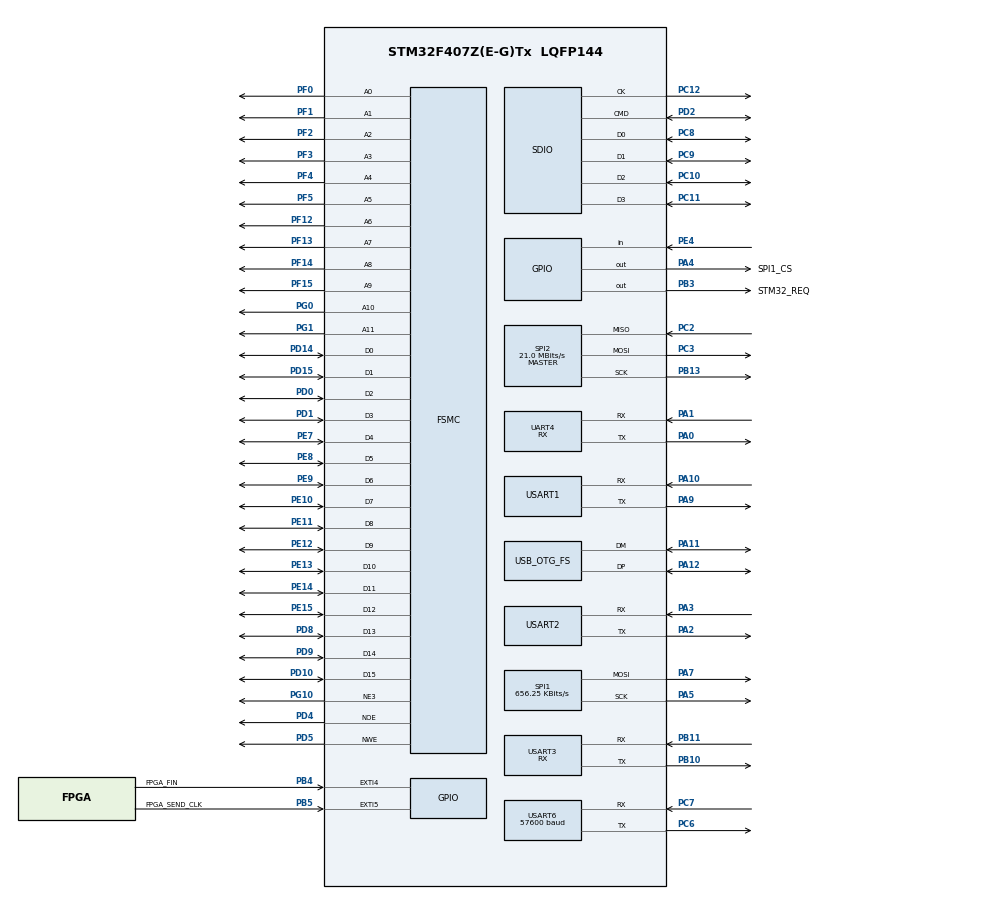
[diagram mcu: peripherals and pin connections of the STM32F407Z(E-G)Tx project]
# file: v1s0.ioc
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Dma.Request0=USART1_RX
Dma.Request1=SDIO_RX
Dma.Request2=SDIO_TX
Dma.Request3=USART1_TX
Dma.Request4=USART3_RX
Dma.Request5=UART4_RX
Dma.Request6=USART6_RX
Dma.SDIO_RX.1.Direction=DMA_PERIPH_TO_MEMORY
Dma.SDIO_RX.1.FIFOMode=DMA_FIFOMODE_ENABLE
Dma.SDIO_RX.1.FIFOThreshold=DMA_FIFO_THRESHOLD_FULL
Dma.SDIO_RX.1.Instance=DMA2_Stream3
Dma.SDIO_RX.1.MemBurst=DMA_MBURST_INC4
Dma.SDIO_RX.1.MemDataAlignment=DMA_MDATAALIGN_WORD
Dma.SDIO_RX.1.MemInc=DMA_MINC_ENABLE
Dma.SDIO_RX.1.Mode=DMA_PFCTRL
Dma.SDIO_RX.1.PeriphBurst=DMA_PBURST_INC4
Dma.SDIO_RX.1.PeriphDataAlignment=DMA_PDATAALIGN_WORD
Dma.SDIO_RX.1.PeriphInc=DMA_PINC_DISABLE
Dma.SDIO_RX.1.Priority=DMA_PRIORITY_VERY_HIGH
Dma.SDIO_TX.2.Direction=DMA_MEMORY_TO_PERIPH
Dma.SDIO_TX.2.FIFOMode=DMA_FIFOMODE_ENABLE
Dma.SDIO_TX.2.FIFOThreshold=DMA_FIFO_THRESHOLD_FULL
Dma.SDIO_TX.2.Instance=DMA2_Stream6
Dma.SDIO_TX.2.MemBurst=DMA_MBURST_INC4
Dma.SDIO_TX.2.MemDataAlignment=DMA_MDATAALIGN_WORD
Dma.SDIO_TX.2.MemInc=DMA_MINC_ENABLE
Dma.SDIO_TX.2.Mode=DMA_PFCTRL
Dma.SDIO_TX.2.PeriphBurst=DMA_PBURST_INC4
Dma.SDIO_TX.2.PeriphDataAlignment=DMA_PDATAALIGN_WORD
Dma.SDIO_TX.2.PeriphInc=DMA_PINC_DISABLE
Dma.SDIO_TX.2.Priority=DMA_PRIORITY_VERY_HIGH
Dma.UART4_RX.5.Direction=DMA_PERIPH_TO_MEMORY
Dma.UART4_RX.5.FIFOMode=DMA_FIFOMODE_DISABLE
Dma.UART4_RX.5.Instance=DMA1_Stream2
Dma.UART4_RX.5.MemDataAlignment=DMA_MDATAALIGN_BYTE
Dma.UART4_RX.5.MemInc=DMA_MINC_ENABLE
Dma.UART4_RX.5.Mode=DMA_CIRCULAR
Dma.UART4_RX.5.PeriphDataAlignment=DMA_PDATAALIGN_BYTE
Dma.UART4_RX.5.PeriphInc=DMA_PINC_DISABLE
Dma.UART4_RX.5.Priority=DMA_PRIORITY_MEDIUM
Dma.USART1_RX.0.Direction=DMA_PERIPH_TO_MEMORY
Dma.USART1_RX.0.FIFOMode=DMA_FIFOMODE_DISABLE
Dma.USART1_RX.0.Instance=DMA2_Stream2
Dma.USART1_RX.0.MemDataAlignment=DMA_MDATAALIGN_BYTE
Dma.USART1_RX.0.MemInc=DMA_MINC_ENABLE
Dma.USART1_RX.0.Mode=DMA_CIRCULAR
Dma.USART1_RX.0.PeriphDataAlignment=DMA_PDATAALIGN_BYTE
Dma.USART1_RX.0.PeriphInc=DMA_PINC_DISABLE
Dma.USART1_RX.0.Priority=DMA_PRIORITY_LOW
Dma.USART1_TX.3.Direction=DMA_MEMORY_TO_PERIPH
Dma.USART1_TX.3.FIFOMode=DMA_FIFOMODE_DISABLE
Dma.USART1_TX.3.Instance=DMA2_Stream7
Dma.USART1_TX.3.MemDataAlignment=DMA_MDATAALIGN_BYTE
Dma.USART1_TX.3.MemInc=DMA_MINC_ENABLE
Dma.USART1_TX.3.Mode=DMA_NORMAL
Dma.USART1_TX.3.PeriphDataAlignment=DMA_PDATAALIGN_BYTE
Dma.USART1_TX.3.PeriphInc=DMA_PINC_DISABLE
Dma.USART1_TX.3.Priority=DMA_PRIORITY_LOW
Dma.USART3_RX.4.Direction=DMA_PERIPH_TO_MEMORY
Dma.USART3_RX.4.FIFOMode=DMA_FIFOMODE_DISABLE
Dma.USART3_RX.4.Instance=DMA1_Stream1
Dma.USART3_RX.4.MemDataAlignment=DMA_MDATAALIGN_BYTE
Dma.USART3_RX.4.MemInc=DMA_MINC_ENABLE
Dma.USART3_RX.4.Mode=DMA_CIRCULAR
Dma.USART3_RX.4.PeriphDataAlignment=DMA_PDATAALIGN_BYTE
Dma.USART3_RX.4.PeriphInc=DMA_PINC_DISABLE
Dma.USART3_RX.4.Priority=DMA_PRIORITY_MEDIUM
Dma.USART6_RX.6.Direction=DMA_PERIPH_TO_MEMORY
Dma.USART6_RX.6.FIFOMode=DMA_FIFOMODE_DISABLE
Dma.USART6_RX.6.Instance=DMA2_Stream1
Dma.USART6_RX.6.MemDataAlignment=DMA_MDATAALIGN_BYTE
Dma.USART6_RX.6.MemInc=DMA_MINC_ENABLE
Dma.USART6_RX.6.Mode=DMA_CIRCULAR
Dma.USART6_RX.6.PeriphDataAlignment=DMA_PDATAALIGN_BYTE
Dma.USART6_RX.6.PeriphInc=DMA_PINC_DISABLE
Dma.USART6_RX.6.Priority=DMA_PRIORITY_HIGH
FATFS.BSP.number=1
FATFS.USE_DMA_CODE_SD=1
FATFS._CODE_PAGE=936
FATFS._USE_LFN=2
FATFS0.BSP.STBoard=false
FATFS0.BSP.api=Unknown
FATFS0.BSP.i2caddr=0
FATFS0.BSP.instance=PE4
FATFS0.BSP.ip=GPIO
FATFS0.BSP.mode=Input
FATFS0.BSP.name=Detect_SDIO
FATFS0.BSP.solution=PE4
FSMC.AddressSetupTime1=0
FSMC.BusTurnAroundDuration1=0
FSMC.DataSetupTime1=8
FSMC.ExtendedMode1=FSMC_EXTENDED_MODE_DISABLE
FSMC.WriteOperation1=FSMC_WRITE_OPERATION_ENABLE
Mcu.Family=STM32F4
Mcu.Name=STM32F407Z(E-G)Tx
Mcu.Package=LQFP144
NVIC.DMA1_Stream1_IRQn=true\:7\:0\:true\:false\:true\:false\:true
NVIC.DMA1_Stream2_IRQn=true\:7\:0\:true\:false\:true\:false\:true
NVIC.DMA2_Stream1_IRQn=true\:6\:0\:true\:false\:true\:false\:true
NVIC.DMA2_Stream2_IRQn=true\:15\:0\:true\:false\:true\:false\:true
NVIC.DMA2_Stream3_IRQn=true\:3\:0\:true\:false\:true\:false\:true
NVIC.DMA2_Stream6_IRQn=true\:3\:0\:true\:false\:true\:false\:true
NVIC.DMA2_Stream7_IRQn=true\:15\:0\:true\:false\:true\:false\:true
NVIC.EXTI4_IRQn=true\:0\:0\:true\:false\:true\:true\:true
NVIC.EXTI9_5_IRQn=true\:5\:0\:true\:false\:true\:true\:true
NVIC.OTG_FS_IRQn=true\:14\:0\:true\:false\:true\:true\:true
NVIC.PriorityGroup=NVIC_PRIORITYGROUP_4
NVIC.SDIO_IRQn=true\:2\:0\:true\:false\:true\:true\:true
NVIC.TIM2_IRQn=true\:4\:0\:true\:false\:true\:true\:true
NVIC.UART4_IRQn=true\:7\:0\:true\:false\:true\:true\:true
NVIC.USART1_IRQn=true\:15\:0\:true\:false\:true\:true\:true
NVIC.USART3_IRQn=true\:7\:0\:true\:false\:true\:true\:true
NVIC.USART6_IRQn=true\:6\:0\:true\:false\:true\:true\:true
PA0-WKUP.Mode=Asynchronous
PA0-WKUP.Signal=UART4_TX
PA1.Mode=Asynchronous
PA1.Signal=UART4_RX
PA10.Mode=Asynchronous
PA10.Signal=USART1_RX
PA11.Mode=Device_Only
PA11.Signal=USB_OTG_FS_DM
PA12.Mode=Device_Only
PA12.Signal=USB_OTG_FS_DP
PA13.Mode=Serial_Wire
PA13.Signal=SYS_JTMS-SWDIO
PA14.Mode=Serial_Wire
PA14.Signal=SYS_JTCK-SWCLK
PA2.Mode=Asynchronous
PA2.Signal=USART2_TX
PA3.Mode=Asynchronous
PA3.Signal=USART2_RX
PA4.GPIO_Label=SPI1_CS
PA4.Signal=GPIO_Output
PA5.Mode=TX_Only_Simplex_Unidirect_Master
PA5.Signal=SPI1_SCK
PA7.GPIO_PuPd=GPIO_PULLUP
PA7.Mode=TX_Only_Simplex_Unidirect_Master
PA7.Signal=SPI1_MOSI
PA9.Mode=Asynchronous
PA9.Signal=USART1_TX
PB10.Mode=Asynchronous
PB10.Signal=USART3_TX
PB11.Mode=Asynchronous
PB11.Signal=USART3_RX
PB13.Mode=Full_Duplex_Master
PB13.Signal=SPI2_SCK
PB3.GPIO_Label=STM32_REQ
PB3.GPIO_PuPd=GPIO_PULLUP
PB3.GPIO_Speed=GPIO_SPEED_FREQ_VERY_HIGH
PB3.PinState=GPIO_PIN_SET
PB3.Signal=GPIO_Output
PB4.GPIO_Label=FPGA_FIN
PB4.GPIO_ModeDefaultEXTI=GPIO_MODE_IT_RISING
PB4.GPIO_PuPd=GPIO_NOPULL
PB4.Signal=GPXTI4
PB5.GPIO_Label=FPGA_SEND_CLK
PB5.GPIO_PuPd=GPIO_NOPULL
PB5.Signal=GPXTI5
PC10.GPIO_PuPd=GPIO_NOPULL
PC10.Mode=SD_4_bits_Wide_bus
PC10.Signal=SDIO_D2
PC11.GPIO_PuPd=GPIO_NOPULL
PC11.Mode=SD_4_bits_Wide_bus
PC11.Signal=SDIO_D3
PC12.Mode=SD_4_bits_Wide_bus
PC12.Signal=SDIO_CK
PC14-OSC32_IN.Mode=LSE-External-Oscillator
PC14-OSC32_IN.Signal=RCC_OSC32_IN
PC15-OSC32_OUT.Mode=LSE-External-Oscillator
PC15-OSC32_OUT.Signal=RCC_OSC32_OUT
PC2.Mode=Full_Duplex_Master
PC2.Signal=SPI2_MISO
PC3.Mode=Full_Duplex_Master
PC3.Signal=SPI2_MOSI
PC6.Mode=Asynchronous
PC6.Signal=USART6_TX
PC7.Mode=Asynchronous
PC7.Signal=USART6_RX
PC8.GPIO_PuPd=GPIO_NOPULL
PC8.Mode=SD_4_bits_Wide_bus
PC8.Signal=SDIO_D0
PC9.GPIO_PuPd=GPIO_NOPULL
PC9.Mode=SD_4_bits_Wide_bus
PC9.Signal=SDIO_D1
PD0.GPIO_PuPd=GPIO_PULLUP
PD0.Signal=FSMC_D2_DA2
PD1.GPIO_PuPd=GPIO_PULLUP
PD1.Signal=FSMC_D3_DA3
PD10.Signal=FSMC_D15_DA15
PD14.GPIO_PuPd=GPIO_PULLUP
PD14.Signal=FSMC_D0_DA0
PD15.GPIO_PuPd=GPIO_PULLUP
PD15.Signal=FSMC_D1_DA1
PD2.GPIO_PuPd=GPIO_NOPULL
PD2.Mode=SD_4_bits_Wide_bus
PD2.Signal=SDIO_CMD
PD4.GPIO_PuPd=GPIO_PULLUP
PD4.Signal=FSMC_NOE
PD5.GPIO_PuPd=GPIO_PULLUP
PD5.Signal=FSMC_NWE
PD8.Signal=FSMC_D13_DA13
PD9.Signal=FSMC_D14_DA14
PE10.GPIO_PuPd=GPIO_PULLUP
PE10.Signal=FSMC_D7_DA7
PE11.Signal=FSMC_D8_DA8
PE12.Signal=FSMC_D9_DA9
PE13.Signal=FSMC_D10_DA10
PE14.Signal=FSMC_D11_DA11
PE15.Signal=FSMC_D12_DA12
PE4.GPIO_PuPd=GPIO_PULLDOWN
PE4.Signal=GPIO_Input
PE7.GPIO_PuPd=GPIO_PULLUP
PE7.Signal=FSMC_D4_DA4
PE8.GPIO_PuPd=GPIO_PULLUP
PE8.Signal=FSMC_D5_DA5
PE9.GPIO_PuPd=GPIO_PULLUP
PE9.Signal=FSMC_D6_DA6
PF0.GPIO_PuPd=GPIO_PULLUP
PF0.Signal=FSMC_A0
PF1.GPIO_PuPd=GPIO_PULLUP
PF1.Signal=FSMC_A1
PF12.Signal=FSMC_A6
PF13.Signal=FSMC_A7
PF14.Signal=FSMC_A8
PF15.Signal=FSMC_A9
PF2.GPIO_PuPd=GPIO_PULLUP
PF2.Signal=FSMC_A2
PF3.Signal=FSMC_A3
PF4.Signal=FSMC_A4
PF5.Signal=FSMC_A5
PG0.Signal=FSMC_A10
PG1.Signal=FSMC_A11
PG10.GPIO_PuPd=GPIO_PULLUP
PG10.Mode=NorPsramChipSelect3_1
PG10.Signal=FSMC_NE3
PH0-OSC_IN.Mode=HSE-External-Oscillator
PH0-OSC_IN.Signal=RCC_OSC_IN
PH1-OSC_OUT.Mode=HSE-External-Oscillator
PH1-OSC_OUT.Signal=RCC_OSC_OUT
ProjectManager.HeapSize=0x1000
ProjectManager.StackSize=0x1000
ProjectManager.TargetToolchain=SW4STM32
RCC.48MHZClocksFreq_Value=48000000
RCC.AHBFreq_Value=168000000
RCC.APB1CLKDivider=RCC_HCLK_DIV4
RCC.APB1Freq_Value=42000000
RCC.APB1TimFreq_Value=84000000
RCC.APB2CLKDivider=RCC_HCLK_DIV2
RCC.APB2Freq_Value=84000000
RCC.APB2TimFreq_Value=168000000
RCC.CortexFreq_Value=168000000
RCC.HCLKFreq_Value=168000000
RCC.HSE_VALUE=25000000
RCC.HSI_VALUE=16000000
RCC.PLLM=25
RCC.PLLN=336
RCC.PLLQ=7
RCC.RCC_RTC_Clock_Source=RCC_RTCCLKSOURCE_LSE
RCC.RCC_RTC_Clock_SourceVirtual=RCC_RTCCLKSOURCE_LSE
RCC.SYSCLKFreq_VALUE=168000000
RCC.SYSCLKSource=RCC_SYSCLKSOURCE_PLLCLK
RCC.VCOOutputFreq_Value=336000000
RTC.Date=19
RTC.Format=RTC_FORMAT_BCD
RTC.Hours=17
RTC.Minutes=40
RTC.Month=RTC_MONTH_JULY
RTC.WeekDay=RTC_WEEKDAY_TUESDAY
RTC.Year=22
SDIO.ClockDiv=2
SH.FSMC_A0.0=FSMC_A0,12b-a1
SH.FSMC_A1.0=FSMC_A1,12b-a1
SH.FSMC_A10.0=FSMC_A10,12b-a1
SH.FSMC_A11.0=FSMC_A11,12b-a1
SH.FSMC_A2.0=FSMC_A2,12b-a1
SH.FSMC_A3.0=FSMC_A3,12b-a1
SH.FSMC_A4.0=FSMC_A4,12b-a1
SH.FSMC_A5.0=FSMC_A5,12b-a1
SH.FSMC_A6.0=FSMC_A6,12b-a1
SH.FSMC_A7.0=FSMC_A7,12b-a1
SH.FSMC_A8.0=FSMC_A8,12b-a1
SH.FSMC_A9.0=FSMC_A9,12b-a1
SH.FSMC_D0_DA0.0=FSMC_D0,16b-d1
SH.FSMC_D10_DA10.0=FSMC_D10,16b-d1
SH.FSMC_D11_DA11.0=FSMC_D11,16b-d1
SH.FSMC_D12_DA12.0=FSMC_D12,16b-d1
SH.FSMC_D13_DA13.0=FSMC_D13,16b-d1
SH.FSMC_D14_DA14.0=FSMC_D14,16b-d1
SH.FSMC_D15_DA15.0=FSMC_D15,16b-d1
SH.FSMC_D1_DA1.0=FSMC_D1,16b-d1
SH.FSMC_D2_DA2.0=FSMC_D2,16b-d1
SH.FSMC_D3_DA3.0=FSMC_D3,16b-d1
SH.FSMC_D4_DA4.0=FSMC_D4,16b-d1
SH.FSMC_D5_DA5.0=FSMC_D5,16b-d1
SH.FSMC_D6_DA6.0=FSMC_D6,16b-d1
SH.FSMC_D7_DA7.0=FSMC_D7,16b-d1
SH.FSMC_D8_DA8.0=FSMC_D8,16b-d1
SH.FSMC_D9_DA9.0=FSMC_D9,16b-d1
SH.FSMC_NOE.0=FSMC_NOE,Sram1
SH.FSMC_NWE.0=FSMC_NWE,Sram1
SPI1.BaudRatePrescaler=SPI_BAUDRATEPRESCALER_128
SPI1.CalculateBaudRate=656.25 KBits/s
SPI1.Direction=SPI_DIRECTION_2LINES
SPI1.Mode=SPI_MODE_MASTER
SPI1.VirtualType=VM_MASTER
SPI2.CalculateBaudRate=21.0 MBits/s
SPI2.Direction=SPI_DIRECTION_2LINES
SPI2.Mode=SPI_MODE_MASTER
SPI2.VirtualType=VM_MASTER
TIM2.Period=9
TIM2.Prescaler=8399
UART4.Mode=MODE_RX
UART4.VirtualMode=Asynchronous
USART1.VirtualMode=VM_ASYNC
USART2.VirtualMode=VM_ASYNC
USART3.Mode=MODE_RX
USART3.VirtualMode=VM_ASYNC
USART6.BaudRate=57600
USART6.VirtualMode=VM_ASYNC
USB_DEVICE.CLASS_NAME_FS=CDC
USB_DEVICE.VirtualMode-CDC_FS=Cdc
USB_DEVICE.VirtualModeFS=Cdc_FS
USB_OTG_FS.VirtualMode=Device_Only
VP_FATFS_VS_SDIO.Mode=SDIO
VP_RTC_VS_RTC_Activate.Mode=RTC_Enabled
VP_RTC_VS_RTC_Calendar.Mode=RTC_Calendar
VP_TIM1_VS_ClockSourceINT.Mode=Internal
VP_TIM2_VS_ClockSourceINT.Mode=Internal
VP_USB_DEVICE_VS_USB_DEVICE_CDC_FS.Mode=CDC_FS
board=custom

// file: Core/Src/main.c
/* USER CODE BEGIN Header */
/**
  ******************************************************************************
  * @file           : main.c
  * @brief          : Main program body
  ******************************************************************************
  * @attention
  *
  * <h2><center>&copy; Copyright (c) 2022 STMicroelectronics.
  * All rights reserved.</center></h2>
  *
  * This software component is licensed by ST under Ultimate Liberty license
  * SLA0044, the "License"; You may not use this file except in compliance with
  * the License. You may obtain a copy of the License at:
  *                             www.st.com/SLA0044
  *
  ******************************************************************************
  */
/* USER CODE END Header */
#include "main.h"
#include "dma.h"
#include "fatfs.h"
#include "rtc.h"
#include "sdio.h"
#include "spi.h"
#include "tim.h"
#include "usart.h"
#include "usb_device.h"
#include "gpio.h"
#include "fsmc.h"

/* USER CODE BEGIN Includes */
#include "fsmc2fpga.h"
#include "usbd_cdc_if.h"
#include "tool.h"
#include "config.h"
#include "sd_data.h"
#include "retarget.h"
#include "tempacket.h"
/* USER CODE END Includes */

/* USER CODE BEGIN PD */
#define Bank1_SRAM1_ADDR    ((uint32_t)(0x60000000))
/* USER CODE END PD */

/* USER CODE BEGIN PV */
extern uint8_t cnt;

/* 控制串口发送速率 */
uint32_t Monitor_Send_Tick = 0;
uint32_t Monitor_Send_Delay = 1;

/* USER CODE END PV */

void SystemClock_Config(void);

int main(void)
{

    /* MCU Configuration--------------------------------------------------------*/

    /* Reset of all peripherals, Initializes the Flash interface and the Systick. */
    HAL_Init();

    /* Configure the system clock */
    SystemClock_Config();

    /* Initialize all configured peripherals */
    MX_GPIO_Init();
    MX_DMA_Init();
    MX_FSMC_Init();
    MX_USB_DEVICE_Init();
    MX_USART1_UART_Init();
    MX_RTC_Init();
    MX_SDIO_SD_Init();
    MX_SPI1_Init();
    MX_SPI2_Init();
    MX_TIM1_Init();
    MX_UART4_Init();
    MX_USART2_UART_Init();
    MX_USART3_UART_Init();
    MX_USART6_UART_Init();
    MX_FATFS_Init();
    MX_TIM2_Init();
    /* USER CODE BEGIN 2 */

    RetargetInit(&huart1);

    FPGA_Reset();

    //TP_FPGA_Start();
    //LL_mDelay(100);
    //TP_FPGA_Stop();

    SD_DATA_Test();

    printf("Begin Main Task...\r\n");

    /* USER CODE END 2 */

    /* Infinite loop */
    /* USER CODE BEGIN WHILE */
    uint32_t send_index = 0;

    while (1) {

        /* USER CODE END WHILE */

        /* USER CODE BEGIN 3 */

        uint8_t result;
        uint8_t *buffer = FPGA_GetMonitorBuffer();
        Monitor_Send_Delay = 88;
        if (buffer) {
            if (FPGA_SPLITFRAME_FLAG == 1)
            {
                int len = FPGA_GetMonitorBufferLength();
                int s = 128;
                uint8_t *pData;
                int slen;

                while(1) {
                    // 判断是否需要结束分帧传输
                    if(frameStopFlag == 1)
                    {
                        frameStopFlag = 0;
                        frameReqFlag = 0;
                        frameReqNo = 0;
                        FPGA_SPLITFRAME_FLAG = 0;
                        FPGA_ClearMonitorBuffer();
                        break;
                    }

                    // 等待请求分帧数据
                    if (frameReqFlag == 1) {
                        frameReqFlag = 0;

                        // 生成分帧传输帧
                        int k = frameReqNo;

                        slen = len-k*s;
                        // 最后一帧
                        if(slen <= s) {
                            pData = TP_GeneSplitFrameAck((uint8_t *) &buffer[k * s], slen, k, 1);
                        }
                        else {
                            slen = s;
                            pData = TP_GeneSplitFrameAck((uint8_t *) &buffer[k * s], slen, k, 0);
                        }

                        My_USART_Send(USART6, pData, slen + 14);
                        //LL_mDelay(Monitor_Send_Delay);
                    }
                    else
                    {
                        LL_mDelay(1);
                    }
                }
            }
            else {
                // 开始发送
                uint32_t send_cnt = 0;
                //数据
                int len = FPGA_GetMonitorBufferLength();
                int s = 128;
                int m = len / s;
                int n = len % s;

                for (int k = 0; k < m; k++) {
                    //停止状态 退出发送状态
                    if (0 == ADC_FPGA_Status) break;
                    // 发送数据到USB
                    if (ADC_Sample_DataChannel == ADC_SAMPLE_DATA_CHANNEL_USB) {
                        do {
                            result = CDC_Transmit_FS((uint8_t *) &buffer[k * s], s);
                            LL_mDelay(1);
                        } while (result == USBD_BUSY);
                    } else {
                        My_USART_Send(USART6, (uint8_t *) &buffer[k * s], s);
                        LL_mDelay(Monitor_Send_Delay);
                    }
                    send_cnt += s;

                }
                if (n) {
                    //停止状态 退出发送状态
                    if (0 == ADC_FPGA_Status) continue;

                    // 发送数据到USB
                    if (ADC_Sample_DataChannel == ADC_SAMPLE_DATA_CHANNEL_USB) {
                        do {
                            result = CDC_Transmit_FS((uint8_t *) &buffer[m * s], n);
                            LL_mDelay(1);
                        } while (result == USBD_BUSY);
                    } else {
                        My_USART_Send(USART6, (uint8_t *) &buffer[m * s], n);
                        LL_mDelay(Monitor_Send_Delay);
                    }
                    send_cnt += s;
                }
                FPGA_ClearMonitorBuffer();
            }
        }
    }
    /* USER CODE END 3 */
}

void SystemClock_Config(void)
{
    RCC_OscInitTypeDef RCC_OscInitStruct = {0};
    RCC_ClkInitTypeDef RCC_ClkInitStruct = {0};
    RCC_PeriphCLKInitTypeDef PeriphClkInitStruct = {0};

    /** Configure the main internal regulator output voltage
    */
    __HAL_RCC_PWR_CLK_ENABLE();
    __HAL_PWR_VOLTAGESCALING_CONFIG(PWR_REGULATOR_VOLTAGE_SCALE1);

    // 先将时钟源选择为内部时钟
    RCC_ClkInitStruct.ClockType = RCC_CLOCKTYPE_SYSCLK;
    RCC_ClkInitStruct.SYSCLKSource = RCC_SYSCLKSOURCE_HSI;
    if (HAL_RCC_ClockConfig(&RCC_ClkInitStruct, FLASH_LATENCY_5) != HAL_OK)
    {
        Error_Handler();
    }
    /** Initializes the RCC Oscillators according to the specified parameters
    * in the RCC_OscInitTypeDef structure.
    */
    RCC_OscInitStruct.OscillatorType = RCC_OSCILLATORTYPE_HSE|RCC_OSCILLATORTYPE_LSE;
    RCC_OscInitStruct.HSEState = RCC_HSE_ON;
    RCC_OscInitStruct.LSEState = RCC_LSE_ON;
    RCC_OscInitStruct.PLL.PLLState = RCC_PLL_ON;
    RCC_OscInitStruct.PLL.PLLSource = RCC_PLLSOURCE_HSE;
    RCC_OscInitStruct.PLL.PLLM = 25;
    RCC_OscInitStruct.PLL.PLLN = 336;
    RCC_OscInitStruct.PLL.PLLP = RCC_PLLP_DIV2;
    RCC_OscInitStruct.PLL.PLLQ = 7;
    if (HAL_RCC_OscConfig(&RCC_OscInitStruct) != HAL_OK)
    {
        Error_Handler();
    }
    /** Initializes the CPU, AHB and APB buses clocks
    */
    RCC_ClkInitStruct.ClockType = RCC_CLOCKTYPE_HCLK|RCC_CLOCKTYPE_SYSCLK
                                  |RCC_CLOCKTYPE_PCLK1|RCC_CLOCKTYPE_PCLK2;
    RCC_ClkInitStruct.SYSCLKSource = RCC_SYSCLKSOURCE_PLLCLK;
    RCC_ClkInitStruct.AHBCLKDivider = RCC_SYSCLK_DIV1;
    RCC_ClkInitStruct.APB1CLKDivider = RCC_HCLK_DIV4;
    RCC_ClkInitStruct.APB2CLKDivider = RCC_HCLK_DIV2;

    if (HAL_RCC_ClockConfig(&RCC_ClkInitStruct, FLASH_LATENCY_5) != HAL_OK)
    {
        Error_Handler();
    }
    PeriphClkInitStruct.PeriphClockSelection = RCC_PERIPHCLK_RTC;
    PeriphClkInitStruct.RTCClockSelection = RCC_RTCCLKSOURCE_LSE;
    if (HAL_RCCEx_PeriphCLKConfig(&PeriphClkInitStruct) != HAL_OK)
    {
        Error_Handler();
    }

    // 禁用内部高速时钟
    RCC_OscInitStruct.OscillatorType = RCC_OSCILLATORTYPE_HSI;
    RCC_OscInitStruct.HSIState = RCC_HSI_OFF;
    RCC_OscInitStruct.PLL.PLLState = RCC_PLL_NONE;
    if(HAL_RCC_OscConfig(&RCC_OscInitStruct) != HAL_OK)
    {
        Error_Handler();
    }
}

void Error_Handler(void)
{
    /* USER CODE BEGIN Error_Handler_Debug */
    /* User can add his own implementation to report the HAL error return state */
    __disable_irq();
    while (1)
    {
        LL_mDelay(1000);
    }
    /* USER CODE END Error_Handler_Debug */
}

/************************ (C) COPYRIGHT STMicroelectronics *****END OF FILE****/
